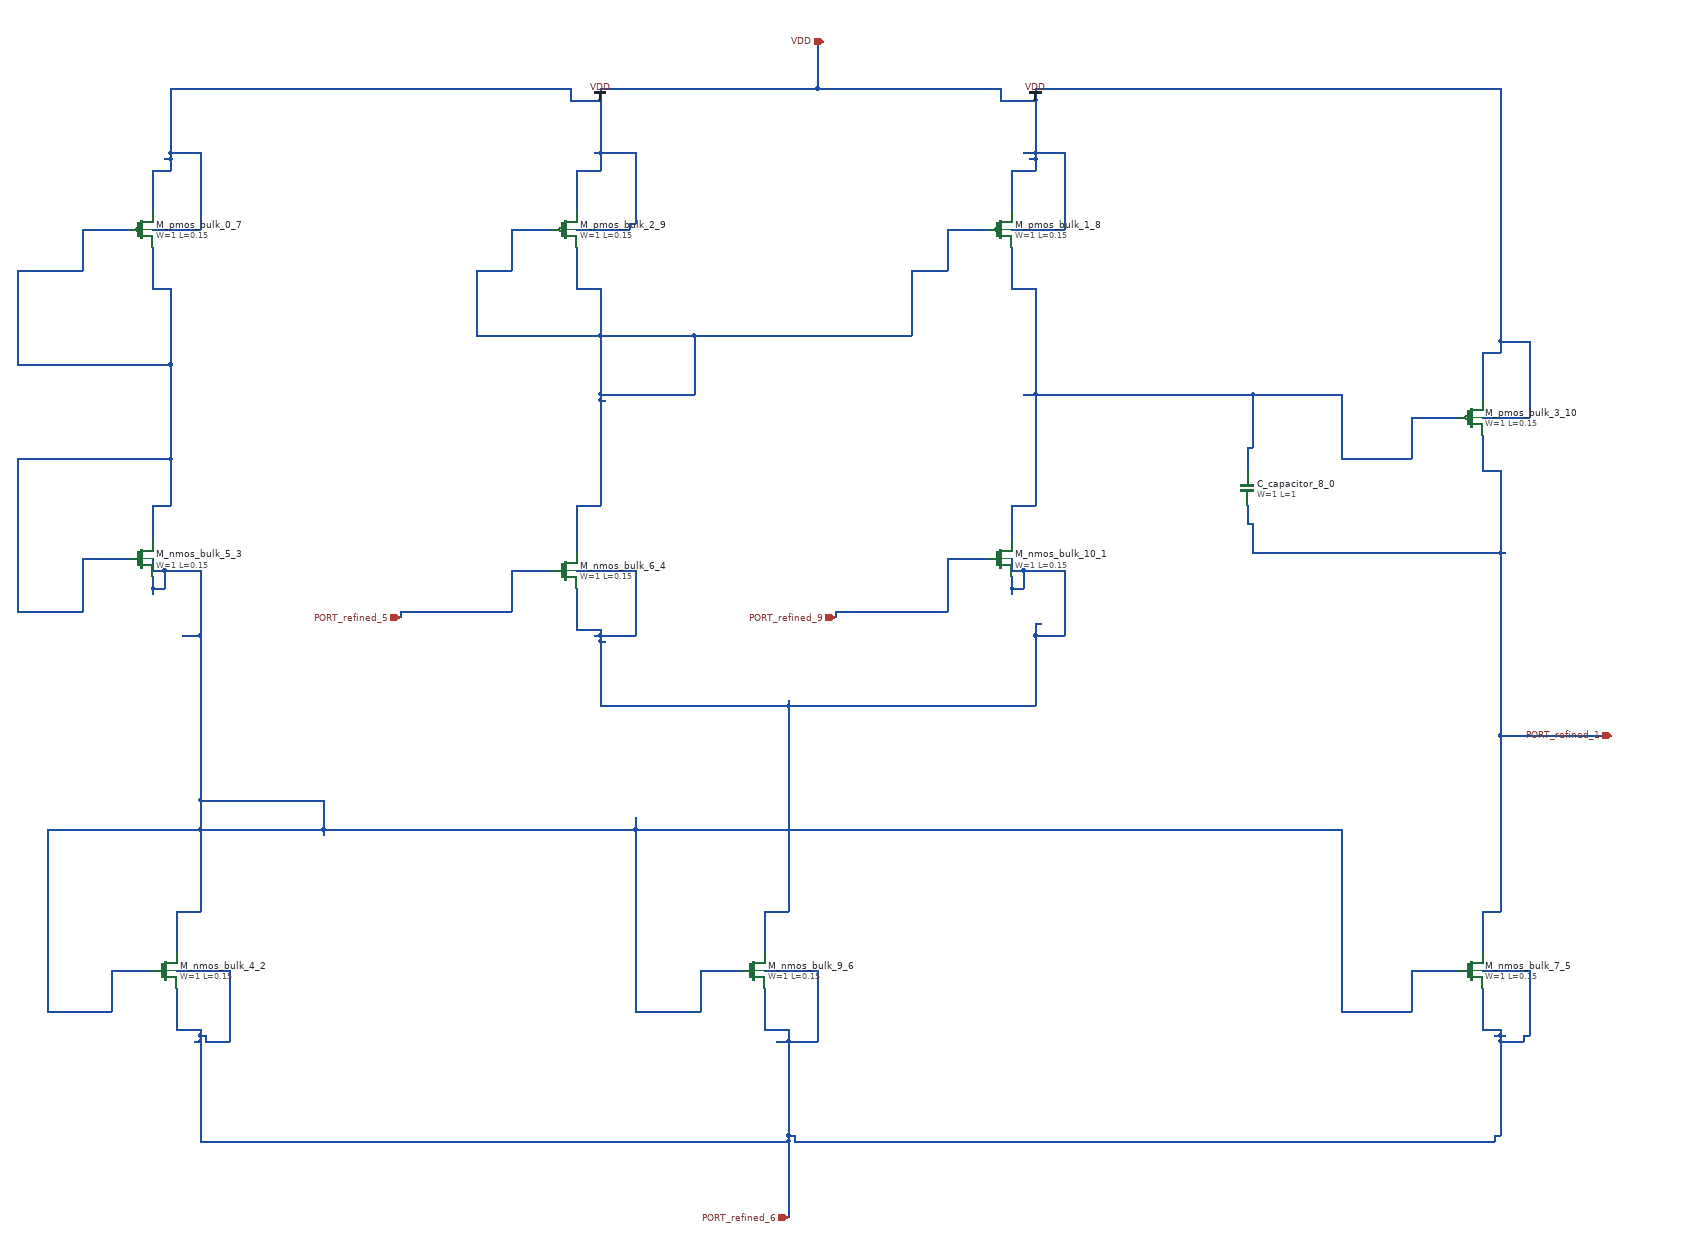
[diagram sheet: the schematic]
v {xschem version=3.4.8 file_version=1.2}
G {}
K {}
V {}
S {}
E {}
C {sky130_fd_pr/cap_mim_m3_1.sym} 2120 880 2 0 {name="C_capacitor_8_0" model=cap_mim_m3_1 W=1 L=1 MF=1 spiceprefix=X}
C {sky130_fd_pr/nfet_01v8.sym} 1700 1000 0 0 {name="M_nmos_bulk_10_1"
W=1
L=0.15
nf=1 
mult=1
ad="expr('int((@nf + 1)/2) * @W / @nf * 0.29')"
pd="expr('2*int((@nf + 1)/2) * (@W / @nf + 0.29)')"
as="expr('int((@nf + 2)/2) * @W / @nf * 0.29')"
ps="expr('2*int((@nf + 2)/2) * (@W / @nf + 0.29)')"
nrd="expr('0.29 / @W ')" nrs="expr('0.29 / @W ')"
sa=0 sb=0 sd=0
model=nfet_01v8
spiceprefix=X
}
C {sky130_fd_pr/nfet_01v8.sym} 280 1700 0 0 {name="M_nmos_bulk_4_2"
W=1
L=0.15
nf=1 
mult=1
ad="expr('int((@nf + 1)/2) * @W / @nf * 0.29')"
pd="expr('2*int((@nf + 1)/2) * (@W / @nf + 0.29)')"
as="expr('int((@nf + 2)/2) * @W / @nf * 0.29')"
ps="expr('2*int((@nf + 2)/2) * (@W / @nf + 0.29)')"
nrd="expr('0.29 / @W ')" nrs="expr('0.29 / @W ')"
sa=0 sb=0 sd=0
model=nfet_01v8
spiceprefix=X
}
C {sky130_fd_pr/nfet_01v8.sym} 240 1000 0 0 {name="M_nmos_bulk_5_3"
W=1
L=0.15
nf=1 
mult=1
ad="expr('int((@nf + 1)/2) * @W / @nf * 0.29')"
pd="expr('2*int((@nf + 1)/2) * (@W / @nf + 0.29)')"
as="expr('int((@nf + 2)/2) * @W / @nf * 0.29')"
ps="expr('2*int((@nf + 2)/2) * (@W / @nf + 0.29)')"
nrd="expr('0.29 / @W ')" nrs="expr('0.29 / @W ')"
sa=0 sb=0 sd=0
model=nfet_01v8
spiceprefix=X
}
C {sky130_fd_pr/nfet_01v8.sym} 960 1020 0 0 {name="M_nmos_bulk_6_4"
W=1
L=0.15
nf=1 
mult=1
ad="expr('int((@nf + 1)/2) * @W / @nf * 0.29')"
pd="expr('2*int((@nf + 1)/2) * (@W / @nf + 0.29)')"
as="expr('int((@nf + 2)/2) * @W / @nf * 0.29')"
ps="expr('2*int((@nf + 2)/2) * (@W / @nf + 0.29)')"
nrd="expr('0.29 / @W ')" nrs="expr('0.29 / @W ')"
sa=0 sb=0 sd=0
model=nfet_01v8
spiceprefix=X
}
C {sky130_fd_pr/nfet_01v8.sym} 2500 1700 0 0 {name="M_nmos_bulk_7_5"
W=1
L=0.15
nf=1 
mult=1
ad="expr('int((@nf + 1)/2) * @W / @nf * 0.29')"
pd="expr('2*int((@nf + 1)/2) * (@W / @nf + 0.29)')"
as="expr('int((@nf + 2)/2) * @W / @nf * 0.29')"
ps="expr('2*int((@nf + 2)/2) * (@W / @nf + 0.29)')"
nrd="expr('0.29 / @W ')" nrs="expr('0.29 / @W ')"
sa=0 sb=0 sd=0
model=nfet_01v8
spiceprefix=X
}
C {sky130_fd_pr/nfet_01v8.sym} 1280 1700 0 0 {name="M_nmos_bulk_9_6"
W=1
L=0.15
nf=1 
mult=1
ad="expr('int((@nf + 1)/2) * @W / @nf * 0.29')"
pd="expr('2*int((@nf + 1)/2) * (@W / @nf + 0.29)')"
as="expr('int((@nf + 2)/2) * @W / @nf * 0.29')"
ps="expr('2*int((@nf + 2)/2) * (@W / @nf + 0.29)')"
nrd="expr('0.29 / @W ')" nrs="expr('0.29 / @W ')"
sa=0 sb=0 sd=0
model=nfet_01v8
spiceprefix=X
}
C {sky130_fd_pr/pfet_01v8.sym} 240 440 0 0 {name="M_pmos_bulk_0_7"
W=1
L=0.15
nf=1
mult=1
ad="expr('int((@nf + 1)/2) * @W / @nf * 0.29')"
pd="expr('2*int((@nf + 1)/2) * (@W / @nf + 0.29)')"
as="expr('int((@nf + 2)/2) * @W / @nf * 0.29')"
ps="expr('2*int((@nf + 2)/2) * (@W / @nf + 0.29)')"
nrd="expr('0.29 / @W ')" nrs="expr('0.29 / @W ')"
sa=0 sb=0 sd=0
model=pfet_01v8
spiceprefix=X
}
C {sky130_fd_pr/pfet_01v8.sym} 1700 440 0 0 {name="M_pmos_bulk_1_8"
W=1
L=0.15
nf=1
mult=1
ad="expr('int((@nf + 1)/2) * @W / @nf * 0.29')"
pd="expr('2*int((@nf + 1)/2) * (@W / @nf + 0.29)')"
as="expr('int((@nf + 2)/2) * @W / @nf * 0.29')"
ps="expr('2*int((@nf + 2)/2) * (@W / @nf + 0.29)')"
nrd="expr('0.29 / @W ')" nrs="expr('0.29 / @W ')"
sa=0 sb=0 sd=0
model=pfet_01v8
spiceprefix=X
}
C {sky130_fd_pr/pfet_01v8.sym} 960 440 0 0 {name="M_pmos_bulk_2_9"
W=1
L=0.15
nf=1
mult=1
ad="expr('int((@nf + 1)/2) * @W / @nf * 0.29')"
pd="expr('2*int((@nf + 1)/2) * (@W / @nf + 0.29)')"
as="expr('int((@nf + 2)/2) * @W / @nf * 0.29')"
ps="expr('2*int((@nf + 2)/2) * (@W / @nf + 0.29)')"
nrd="expr('0.29 / @W ')" nrs="expr('0.29 / @W ')"
sa=0 sb=0 sd=0
model=pfet_01v8
spiceprefix=X
}
C {sky130_fd_pr/pfet_01v8.sym} 2500 760 0 0 {name="M_pmos_bulk_3_10"
W=1
L=0.15
nf=1
mult=1
ad="expr('int((@nf + 1)/2) * @W / @nf * 0.29')"
pd="expr('2*int((@nf + 1)/2) * (@W / @nf + 0.29)')"
as="expr('int((@nf + 2)/2) * @W / @nf * 0.29')"
ps="expr('2*int((@nf + 2)/2) * (@W / @nf + 0.29)')"
nrd="expr('0.29 / @W ')" nrs="expr('0.29 / @W ')"
sa=0 sb=0 sd=0
model=pfet_01v8
spiceprefix=X
}
C {devices/ipin.sym} 2740 1300 0 0 {name="p_port_11_11" lab="PORT_refined_1"}
C {devices/ipin.sym} 1400 120 0 0 {name="p_port_12_12" lab="VDD"}
C {devices/ipin.sym} 680 1100 0 0 {name="p_port_13_13" lab="PORT_refined_5"}
C {devices/ipin.sym} 1340 2120 0 0 {name="p_port_14_14" lab="PORT_refined_6"}
C {devices/ipin.sym} 1420 1100 0 0 {name="p_port_15_15" lab="PORT_refined_9"}
C {devices/vdd.sym} 1760 220 0 0 {name="l_vdd_16_16" lab="VDD"}
C {devices/vdd.sym} 1020 220 0 0 {name="l_vdd_17_17" lab="VDD"}
N 1720 910 1760 910 {}
N 2280 830 2400 830 {}
N 2120 810 2130 810 {}
N 2400 760 2480 760 {}
N 1740 720 1760 720 {}
N 1760 720 2130 720 {}
N 2130 720 2280 720 {}
N 1720 540 1760 540 {}
N 1720 970 1720 910 {}
N 1720 540 1720 470 {}
N 1760 910 1760 720 {}
N 1760 720 1760 540 {}
N 2120 850 2120 810 {}
N 2130 810 2130 720 {}
N 2280 830 2280 720 {}
N 2400 830 2400 760 {}
N 2520 1600 2550 1600 {}
N 2550 1300 2740 1300 {}
N 2130 990 2550 990 {}
N 2550 990 2560 990 {}
N 2120 940 2130 940 {}
N 2520 850 2550 850 {}
N 2120 940 2120 910 {}
N 2130 990 2130 940 {}
N 2520 1670 2520 1600 {}
N 2520 850 2520 790 {}
N 2550 1600 2550 1300 {}
N 2550 1300 2550 990 {}
N 2550 990 2550 850 {}
N 30 1090 140 1090 {}
N 140 1000 220 1000 {}
N 260 910 290 910 {}
N 30 830 290 830 {}
N 30 670 290 670 {}
N 260 540 290 540 {}
N 30 510 140 510 {}
N 140 440 220 440 {}
N 30 1090 30 830 {}
N 30 670 30 510 {}
N 140 1090 140 1000 {}
N 140 510 140 440 {}
N 260 970 260 910 {}
N 260 540 260 470 {}
N 290 910 290 830 {}
N 290 830 290 670 {}
N 290 670 290 540 {}
N 1300 1600 1340 1600 {}
N 1020 1250 1340 1250 {}
N 1340 1250 1760 1250 {}
N 1020 1140 1030 1140 {}
N 1010 1130 1020 1130 {}
N 1020 1130 1080 1130 {}
N 1760 1130 1810 1130 {}
N 980 1120 1020 1120 {}
N 1760 1110 1770 1110 {}
N 1720 1050 1740 1050 {}
N 980 1020 1080 1020 {}
N 1720 1020 1740 1020 {}
N 1740 1020 1810 1020 {}
N 980 1120 980 1050 {}
N 1020 1250 1020 1140 {}
N 1020 1140 1020 1130 {}
N 1020 1130 1020 1120 {}
N 1080 1130 1080 1020 {}
N 1300 1670 1300 1600 {}
N 1340 1600 1340 1250 {}
N 1340 1250 1340 1240 {}
N 1720 1060 1720 1050 {}
N 1720 1050 1720 1030 {}
N 1720 1020 1720 1000 {}
N 1740 1050 1740 1020 {}
N 1760 1250 1760 1130 {}
N 1760 1130 1760 1110 {}
N 1810 1130 1810 1020 {}
N 980 910 1020 910 {}
N 1020 730 1030 730 {}
N 1020 720 1180 720 {}
N 810 620 1020 620 {}
N 1020 620 1180 620 {}
N 1180 620 1550 620 {}
N 980 540 1020 540 {}
N 810 510 870 510 {}
N 1550 510 1610 510 {}
N 870 440 940 440 {}
N 1610 440 1680 440 {}
N 810 620 810 510 {}
N 870 510 870 440 {}
N 980 990 980 910 {}
N 980 540 980 470 {}
N 1020 910 1020 730 {}
N 1020 730 1020 720 {}
N 1020 720 1020 620 {}
N 1020 620 1020 540 {}
N 1180 720 1180 620 {}
N 1550 620 1550 510 {}
N 1610 510 1610 440 {}
N 680 1090 870 1090 {}
N 870 1020 940 1020 {}
N 680 1100 680 1090 {}
N 870 1090 870 1020 {}
N 340 1990 1340 1990 {}
N 1350 1990 2540 1990 {}
N 1340 1980 1350 1980 {}
N 2540 1980 2550 1980 {}
N 330 1820 340 1820 {}
N 350 1820 390 1820 {}
N 1320 1820 1340 1820 {}
N 1340 1820 1390 1820 {}
N 2550 1820 2590 1820 {}
N 340 1810 350 1810 {}
N 2540 1810 2550 1810 {}
N 2550 1810 2560 1810 {}
N 2590 1810 2600 1810 {}
N 300 1800 340 1800 {}
N 1300 1800 1340 1800 {}
N 2520 1800 2550 1800 {}
N 300 1700 390 1700 {}
N 1300 1700 1390 1700 {}
N 2520 1700 2600 1700 {}
N 300 1800 300 1730 {}
N 340 1990 340 1820 {}
N 340 1820 340 1810 {}
N 340 1810 340 1800 {}
N 350 1820 350 1810 {}
N 390 1820 390 1700 {}
N 1300 1800 1300 1730 {}
N 1340 2120 1340 1990 {}
N 1340 1990 1340 1980 {}
N 1340 1980 1340 1820 {}
N 1340 1820 1340 1800 {}
N 1350 1990 1350 1980 {}
N 1390 1820 1390 1700 {}
N 2520 1800 2520 1730 {}
N 2540 1990 2540 1980 {}
N 2550 1980 2550 1820 {}
N 2550 1820 2550 1810 {}
N 2550 1810 2550 1800 {}
N 2590 1820 2590 1810 {}
N 2600 1810 2600 1700 {}
N 80 1770 190 1770 {}
N 1080 1770 1190 1770 {}
N 2280 1770 2400 1770 {}
N 190 1700 260 1700 {}
N 1190 1700 1260 1700 {}
N 2400 1700 2480 1700 {}
N 300 1600 340 1600 {}
N 80 1460 340 1460 {}
N 340 1460 550 1460 {}
N 550 1460 1080 1460 {}
N 1080 1460 2280 1460 {}
N 340 1410 550 1410 {}
N 310 1130 340 1130 {}
N 260 1050 280 1050 {}
N 260 1020 280 1020 {}
N 280 1020 340 1020 {}
N 80 1770 80 1460 {}
N 190 1770 190 1700 {}
N 260 1060 260 1050 {}
N 260 1050 260 1030 {}
N 260 1020 260 1000 {}
N 280 1050 280 1020 {}
N 300 1670 300 1600 {}
N 340 1600 340 1460 {}
N 340 1460 340 1410 {}
N 340 1410 340 1130 {}
N 340 1130 340 1020 {}
N 550 1470 550 1460 {}
N 550 1460 550 1410 {}
N 1080 1770 1080 1460 {}
N 1080 1460 1080 1440 {}
N 1190 1770 1190 1700 {}
N 2280 1770 2280 1460 {}
N 2400 1770 2400 1700 {}
N 2520 760 2600 760 {}
N 2520 650 2550 650 {}
N 2550 630 2600 630 {}
N 260 440 340 440 {}
N 980 440 1070 440 {}
N 1720 440 1810 440 {}
N 1070 430 1080 430 {}
N 260 340 290 340 {}
N 980 340 1020 340 {}
N 1720 340 1760 340 {}
N 280 320 290 320 {}
N 1750 320 1760 320 {}
N 290 310 340 310 {}
N 1010 310 1020 310 {}
N 1020 310 1080 310 {}
N 1740 310 1760 310 {}
N 1760 310 1810 310 {}
N 970 220 1020 220 {}
N 1700 220 1760 220 {}
N 290 200 970 200 {}
N 1020 200 1390 200 {}
N 1390 200 1700 200 {}
N 1760 200 2550 200 {}
N 1390 120 1400 120 {}
N 260 410 260 340 {}
N 290 340 290 320 {}
N 290 320 290 310 {}
N 290 310 290 200 {}
N 340 440 340 310 {}
N 970 220 970 200 {}
N 980 410 980 340 {}
N 1020 340 1020 310 {}
N 1020 310 1020 220 {}
N 1020 220 1020 200 {}
N 1070 440 1070 430 {}
N 1080 430 1080 310 {}
N 1390 200 1390 120 {}
N 1700 220 1700 200 {}
N 1720 410 1720 340 {}
N 1760 340 1760 320 {}
N 1760 320 1760 310 {}
N 1760 310 1760 220 {}
N 1760 220 1760 200 {}
N 1810 440 1810 310 {}
N 2520 730 2520 650 {}
N 2550 650 2550 630 {}
N 2550 630 2550 200 {}
N 2600 760 2600 630 {}
N 1420 1090 1610 1090 {}
N 1610 1000 1680 1000 {}
N 1420 1100 1420 1090 {}
N 1610 1090 1610 1000 {}
